VERSION 5.8 ;
BUSBITCHARS "[]" ;
DIVIDERCHAR "/" ;
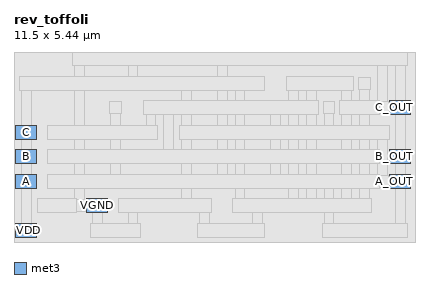
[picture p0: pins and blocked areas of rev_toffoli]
MACRO rev_toffoli
  CLASS BLOCK ;
  ORIGIN 0 0 ;
  FOREIGN rev_toffoli 0 0 ;
  SIZE 11.500 BY 5.440 ;
  SYMMETRY X Y ;
  PIN VDD
    DIRECTION INOUT ;
    USE POWER ;
    PORT
      LAYER met3 ;
      RECT 0.050 0.140 0.650 0.540 ;
    END
  END VDD
  PIN VGND
    DIRECTION INOUT ;
    USE GROUND ;
    PORT
      LAYER met3 ;
      RECT 2.090 0.840 2.690 1.240 ;
    END
  END VGND
  PIN A
    DIRECTION INPUT ;
    USE SIGNAL ;
    PORT
      LAYER met3 ;
      RECT 0.050 1.540 0.650 1.940 ;
    END
  END A
  PIN B
    DIRECTION INPUT ;
    USE SIGNAL ;
    PORT
      LAYER met3 ;
      RECT 0.050 2.240 0.650 2.640 ;
    END
  END B
  PIN C
    DIRECTION INPUT ;
    USE SIGNAL ;
    PORT
      LAYER met3 ;
      RECT 0.050 2.940 0.650 3.340 ;
    END
  END C
  PIN A_OUT
    DIRECTION OUTPUT ;
    USE SIGNAL ;
    PORT
      LAYER met3 ;
      RECT 10.760 1.540 11.360 1.940 ;
    END
  END A_OUT
  PIN B_OUT
    DIRECTION OUTPUT ;
    USE SIGNAL ;
    PORT
      LAYER met3 ;
      RECT 10.760 2.240 11.360 2.640 ;
    END
  END B_OUT
  PIN C_OUT
    DIRECTION OUTPUT ;
    USE SIGNAL ;
    PORT
      LAYER met3 ;
      RECT 10.760 3.640 11.360 4.040 ;
    END
  END C_OUT
  OBS
    LAYER li1 ;
    RECT 0.000 0.000 11.500 5.440 ;
    LAYER met1 ;
    RECT 0.000 0.000 11.500 5.440 ;
    LAYER met2 ;
    RECT 2.205 0.155 2.575 0.525 ;
    RECT 2.250 0.525 2.530 0.870 ;
    RECT 2.220 0.870 2.560 1.210 ;
    RECT 3.225 0.155 3.595 0.525 ;
    RECT 3.270 0.525 3.550 0.870 ;
    RECT 3.240 0.870 3.580 1.210 ;
    RECT 6.795 0.155 7.165 0.525 ;
    RECT 6.840 0.525 7.120 0.870 ;
    RECT 6.810 0.870 7.150 1.210 ;
    RECT 0.675 0.855 1.045 1.225 ;
    RECT 3.735 0.855 4.105 1.225 ;
    RECT 5.265 0.155 5.635 0.525 ;
    RECT 5.310 0.525 5.590 0.855 ;
    RECT 5.265 0.855 5.635 1.225 ;
    RECT 8.835 0.155 9.205 0.525 ;
    RECT 8.880 0.525 9.160 1.570 ;
    RECT 8.850 1.570 9.190 1.910 ;
    RECT 10.380 1.570 10.720 1.910 ;
    RECT 10.410 1.910 10.690 2.955 ;
    RECT 10.365 2.955 10.735 3.325 ;
    RECT 2.715 1.555 3.085 1.925 ;
    RECT 2.760 1.925 3.040 2.270 ;
    RECT 2.730 2.270 3.070 2.610 ;
    RECT 2.760 2.610 3.040 3.670 ;
    RECT 2.730 3.670 3.070 4.010 ;
    RECT 4.245 2.255 4.615 2.625 ;
    RECT 4.290 2.625 4.570 3.670 ;
    RECT 4.260 3.670 4.600 4.010 ;
    RECT 8.835 2.955 9.205 3.325 ;
    RECT 8.880 3.325 9.160 3.670 ;
    RECT 8.850 3.670 9.190 4.010 ;
    RECT 3.735 2.955 4.105 3.325 ;
    RECT 3.780 3.325 4.060 3.655 ;
    RECT 3.735 3.655 4.105 4.025 ;
    RECT 7.320 1.570 7.660 1.910 ;
    RECT 7.350 1.910 7.630 3.655 ;
    RECT 7.305 3.655 7.675 4.025 ;
    RECT 4.770 0.870 5.110 1.210 ;
    RECT 4.800 1.210 5.080 2.955 ;
    RECT 4.755 2.955 5.125 3.325 ;
    RECT 4.800 3.325 5.080 4.370 ;
    RECT 4.770 4.370 5.110 4.710 ;
    RECT 6.285 0.855 6.655 1.225 ;
    RECT 6.330 1.225 6.610 4.370 ;
    RECT 6.300 4.370 6.640 4.710 ;
    RECT 8.340 0.870 8.680 1.210 ;
    RECT 8.370 1.210 8.650 3.655 ;
    RECT 8.325 3.655 8.695 4.025 ;
    RECT 8.370 4.025 8.650 4.370 ;
    RECT 8.340 4.370 8.680 4.710 ;
    RECT 9.855 0.855 10.225 1.225 ;
    RECT 9.900 1.225 10.180 4.370 ;
    RECT 9.870 4.370 10.210 4.710 ;
    RECT 0.165 0.155 0.535 0.525 ;
    RECT 0.210 0.525 0.490 4.355 ;
    RECT 0.165 4.355 0.535 4.725 ;
    RECT 0.675 4.355 1.045 4.725 ;
    RECT 2.205 4.355 2.575 4.725 ;
    RECT 3.735 4.355 4.105 4.725 ;
    RECT 5.265 4.355 5.635 4.725 ;
    RECT 6.795 4.355 7.165 4.725 ;
    RECT 7.830 0.870 8.170 1.210 ;
    RECT 7.860 1.210 8.140 4.355 ;
    RECT 7.815 4.355 8.185 4.725 ;
    RECT 9.360 0.870 9.700 1.210 ;
    RECT 9.390 1.210 9.670 3.655 ;
    RECT 9.345 3.655 9.715 4.025 ;
    RECT 9.390 4.025 9.670 4.355 ;
    RECT 9.345 4.355 9.715 4.725 ;
    RECT 1.710 0.870 2.050 1.210 ;
    RECT 1.740 1.210 2.020 4.370 ;
    RECT 1.710 4.370 2.050 4.710 ;
    RECT 1.740 4.710 2.020 5.055 ;
    RECT 1.695 5.055 2.065 5.425 ;
    RECT 3.240 4.370 3.580 4.710 ;
    RECT 3.270 4.710 3.550 5.055 ;
    RECT 3.225 5.055 3.595 5.425 ;
    RECT 5.790 1.570 6.130 1.910 ;
    RECT 5.820 1.910 6.100 3.670 ;
    RECT 5.790 3.670 6.130 4.010 ;
    RECT 5.820 4.010 6.100 5.055 ;
    RECT 5.775 5.055 6.145 5.425 ;
    RECT 10.380 3.670 10.720 4.010 ;
    RECT 10.410 4.010 10.690 5.055 ;
    RECT 10.365 5.055 10.735 5.425 ;
    RECT 10.875 0.155 11.245 0.525 ;
    RECT 10.920 0.525 11.200 5.055 ;
    RECT 10.875 5.055 11.245 5.425 ;
    LAYER met3 ;
    RECT 2.190 0.140 3.610 0.540 ;
    RECT 5.250 0.140 7.180 0.540 ;
    RECT 8.820 0.140 11.260 0.540 ;
    RECT 0.660 0.840 1.790 1.240 ;
    RECT 2.990 0.840 5.650 1.240 ;
    RECT 6.270 0.840 10.240 1.240 ;
    RECT 0.950 1.540 10.460 1.940 ;
    RECT 0.950 2.240 10.460 2.640 ;
    RECT 0.950 2.940 4.120 3.340 ;
    RECT 4.740 2.940 10.750 3.340 ;
    RECT 3.720 3.640 8.710 4.040 ;
    RECT 9.330 3.640 10.460 4.040 ;
    RECT 0.150 4.340 7.180 4.740 ;
    RECT 7.800 4.340 9.730 4.740 ;
    RECT 1.680 5.040 11.260 5.440 ;
  END
END rev_toffoli
END LIBRARY
